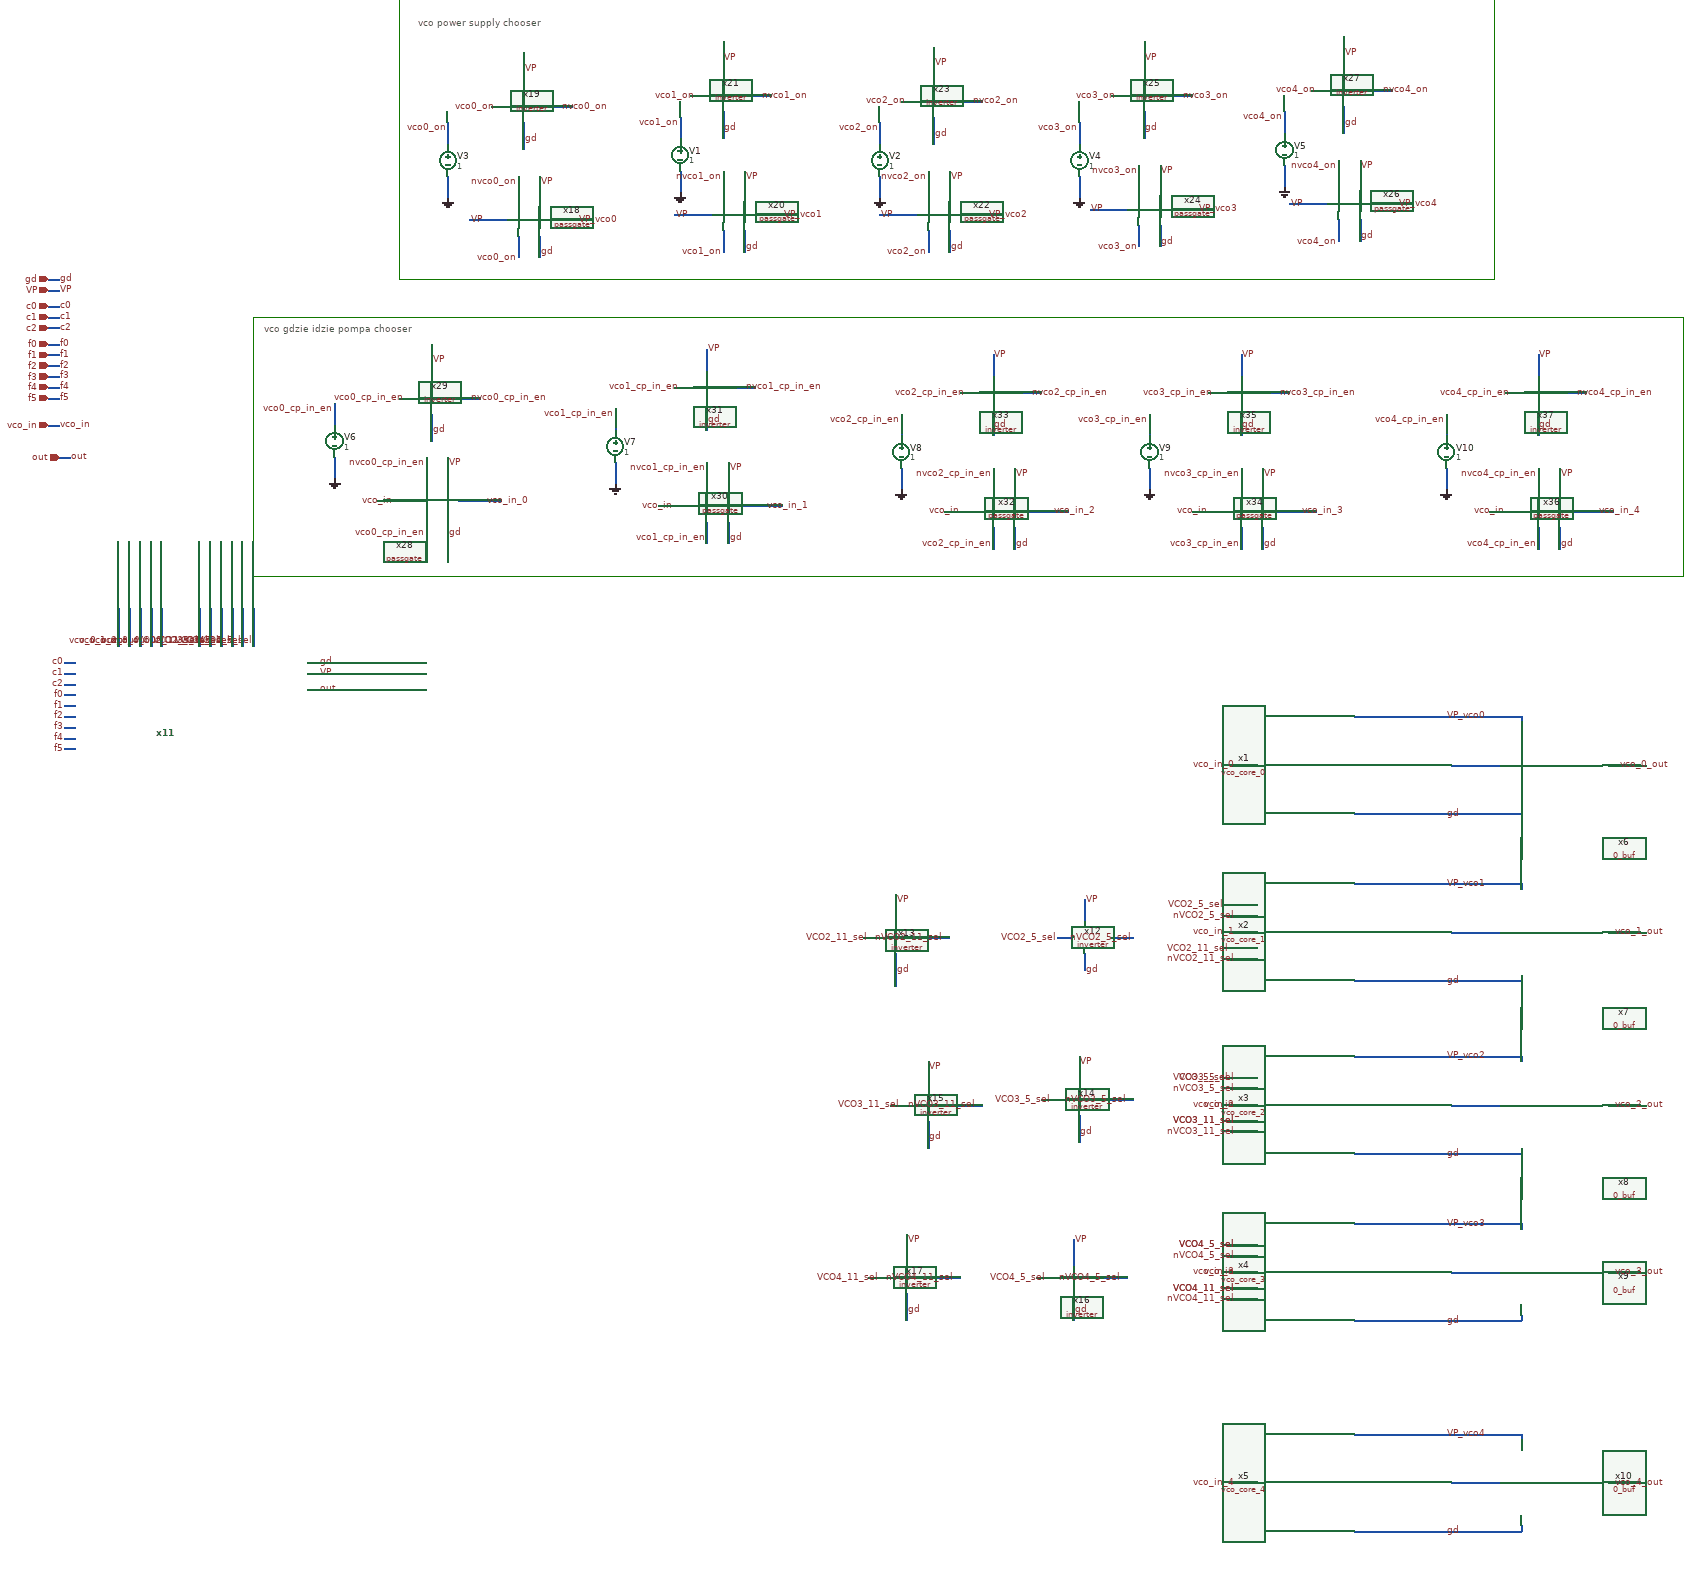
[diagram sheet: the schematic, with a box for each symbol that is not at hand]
v {xschem version=3.4.8RC file_version=1.3}
G {}
K {}
V {}
S {}
F {}
E {}
L 4 -1290 -780 -1290 -340 {}
L 4 -1290 -340 740 -340 {}
L 4 740 -860 740 -340 {}
L 4 -1290 -860 740 -860 {}
L 4 -1290 -860 -1290 -780 {}
P 4 6 -1560 -250 -1560 210 1090 210 1090 -270 -1560 -270 -1560 -250 {}
T {vco power supply chooser} -1253.835345354359 -827.5054171371571 0 0 0.4 0.4 {}
T {vco gdzie idzie pompa chooser} -1540 -260 0 0 0.4 0.4 {}
N 660 560 750 560 {lab=#net1}
N 660 870 750 870 {lab=#net2}
N 660 1190 750 1190 {lab=#net3}
N 660 1500 750 1500 {lab=#net4}
N 660 1890 750 1890 {lab=#net5}
N 950 560 1010 560 {lab=vco_0_out}
N 950 870 1010 870 {lab=vco_1_out}
N 950 1190 1010 1190 {lab=vco_2_out}
N 950 1500 1010 1500 {lab=vco_3_out}
N 950 1890 1010 1890 {lab=vco_4_out}
N -1940 -340 -1920 -340 {lab=gd}
N -1940 -320 -1920 -320 {lab=VP}
N -1940 -270 -1920 -270 {lab=c1}
N -1940 -250 -1920 -250 {lab=c2}
N -1940 -220 -1920 -220 {lab=f0}
N -1940 -200 -1920 -200 {lab=f1}
N -1940 -290 -1920 -290 {lab=c0}
N -1940 -180 -1920 -180 {lab=f2}
N -1940 -160 -1920 -160 {lab=f3}
N -1940 -140 -1920 -140 {lab=f4}
N -1940 -120 -1920 -120 {lab=f5}
N -1460 370 -1440 370 {lab=gd}
N -1460 390 -1440 390 {lab=VP}
N -1920 -10 -1900 -10 {lab=out}
N -1460 420 -1440 420 {lab=out}
N 480 650 790 650 {lab=gd}
N 790 640 790 650 {lab=gd}
N 480 960 790 960 {lab=gd}
N 790 950 790 960 {lab=gd}
N 480 1280 790 1280 {lab=gd}
N 790 1270 790 1280 {lab=gd}
N 790 1580 790 1590 {lab=gd}
N 480 1980 790 1980 {lab=gd}
N 790 1970 790 1980 {lab=gd}
N 480 1800 790 1800 {lab=VP_vco4}
N 790 1800 790 1810 {lab=VP_vco4}
N 480 1410 790 1410 {lab=VP_vco3}
N 790 1410 790 1420 {lab=VP_vco3}
N 480 1100 790 1100 {lab=VP_vco2}
N 790 1100 790 1110 {lab=VP_vco2}
N 480 780 790 780 {lab=VP_vco1}
N 790 780 790 790 {lab=VP_vco1}
N 480 470 790 470 {lab=VP_vco0}
N 790 470 790 480 {lab=VP_vco0}
N 250 900 300 900 {lab=VCO2_11_sel}
N 250 920 300 920 {lab=nVCO2_11_sel}
N 250 1240 300 1240 {lab=nVCO3_11_sel}
N 250 1550 300 1550 {lab=nVCO4_11_sel}
N 250 1890 300 1890 {lab=vco_in}
N 250 560 300 560 {lab=#net6}
N -1660 270 -1660 340 {lab=VCO2_11_sel}
N -1640 270 -1640 340 {lab=VCO2_5_sel}
N -1620 270 -1620 340 {lab=VCO3_11_sel}
N -1600 270 -1600 340 {lab=VCO3_5_sel}
N -1580 270 -1580 340 {lab=VCO4_11_sel}
N -1560 270 -1560 340 {lab=VCO4_5_sel}
N -1810 270 -1810 340 {lab=vco_0_out}
N -1790 270 -1790 340 {lab=vco_1_out}
N -1770 270 -1770 340 {lab=vco_2_out}
N -1750 270 -1750 340 {lab=vco_3_out}
N -1730 270 -1730 340 {lab=vco_4_out}
N -1910 390 -1890 390 {lab=c1}
N -1910 410 -1890 410 {lab=c2}
N -1910 430 -1890 430 {lab=f0}
N -1910 450 -1890 450 {lab=f1}
N -1910 370 -1890 370 {lab=c0}
N -1910 470 -1890 470 {lab=f2}
N -1910 490 -1890 490 {lab=f3}
N -1910 510 -1890 510 {lab=f4}
N -1910 530 -1890 530 {lab=f5}
N -1940 -70 -1920 -70 {lab=vco_in}
N 250 1500 300 1500 {lab=vco_in}
N 250 1190 300 1190 {lab=vco_in}
N 250 870 300 870 {lab=vco_in}
N 480 1590 790 1590 {lab=gd}
N 250 840 300 840 {lab=nVCO2_5_sel}
N 250 1140 300 1140 {lab=VCO3_5_sel}
N 250 1160 300 1160 {lab=nVCO3_5_sel}
N -30 1100 -30 1150 {lab=VP}
N -30 1210 -30 1260 {lab=gd}
N 20 1180 70 1180 {lab=nVCO3_5_sel}
N -100 1180 -50 1180 {lab=VCO3_5_sel}
N -310 1110 -310 1160 {lab=VP}
N -310 1220 -310 1270 {lab=gd}
N -260 1190 -210 1190 {lab=nVCO3_11_sel}
N -380 1190 -330 1190 {lab=VCO3_11_sel}
N 250 1450 300 1450 {lab=VCO4_5_sel}
N 250 1530 300 1530 {lab=VCO4_11_sel}
N 250 1470 300 1470 {lab=nVCO4_5_sel}
N -40 1540 -40 1590 {lab=gd}
N 10 1510 60 1510 {lab=nVCO4_5_sel}
N -110 1510 -60 1510 {lab=VCO4_5_sel}
N -350 1430 -350 1480 {lab=VP}
N -350 1540 -350 1590 {lab=gd}
N -300 1510 -250 1510 {lab=nVCO4_11_sel}
N -420 1510 -370 1510 {lab=VCO4_11_sel}
N -40 1440 -40 1490 {lab=VP}
N -1160 -450 -1090 -450 {lab=VP}
N -1010 -450 -930 -450 {lab=VP_vco0}
N -1120 -660 -1080 -660 {lab=vco0_on}
N -1060 -630 -1060 -580 {lab=gd}
N -1060 -760 -1060 -690 {lab=VP}
N -1010 -660 -970 -660 {lab=nvco0_on}
N -1070 -420 -1070 -380 {lab=vco0_on}
N -1070 -530 -1070 -480 {lab=nvco0_on}
N -1030 -530 -1030 -480 {lab=VP}
N -1030 -420 -1030 -380 {lab=gd}
N -780 -460 -710 -460 {lab=VP}
N -630 -460 -550 -460 {lab=VP_vco1}
N -750 -680 -710 -680 {lab=vco1_on}
N -690 -650 -690 -600 {lab=gd}
N -690 -780 -690 -710 {lab=VP}
N -640 -680 -600 -680 {lab=nvco1_on}
N -690 -430 -690 -390 {lab=vco1_on}
N -690 -540 -690 -490 {lab=nvco1_on}
N -650 -540 -650 -490 {lab=VP}
N -650 -430 -650 -390 {lab=gd}
N -400 -460 -330 -460 {lab=VP}
N -250 -460 -170 -460 {lab=VP_vco2}
N -360 -670 -320 -670 {lab=vco2_on}
N -300 -640 -300 -590 {lab=gd}
N -300 -770 -300 -700 {lab=VP}
N -250 -670 -210 -670 {lab=nvco2_on}
N -310 -430 -310 -390 {lab=vco2_on}
N -310 -540 -310 -490 {lab=nvco2_on}
N -270 -540 -270 -490 {lab=VP}
N -270 -430 -270 -390 {lab=gd}
N -10 -470 60 -470 {lab=VP}
N 140 -470 220 -470 {lab=VP_vco3}
N 30 -680 70 -680 {lab=vco3_on}
N 90 -650 90 -600 {lab=gd}
N 90 -780 90 -710 {lab=VP}
N 140 -680 180 -680 {lab=nvco3_on}
N 80 -440 80 -400 {lab=vco3_on}
N 80 -550 80 -500 {lab=nvco3_on}
N 120 -550 120 -500 {lab=VP}
N 120 -440 120 -400 {lab=gd}
N 360 -480 430 -480 {lab=VP}
N 510 -480 590 -480 {lab=VP_vco4}
N 400 -690 440 -690 {lab=vco4_on}
N 460 -660 460 -610 {lab=gd}
N 460 -790 460 -720 {lab=VP}
N 510 -690 550 -690 {lab=nvco4_on}
N 450 -450 450 -410 {lab=vco4_on}
N 450 -560 450 -510 {lab=nvco4_on}
N 490 -560 490 -510 {lab=VP}
N 490 -450 490 -410 {lab=gd}
N -1200 -530 -1200 -490 {lab=0}
N -1200 -630 -1200 -590 {lab=vco0_on}
N -770 -540 -770 -500 {lab=0}
N -770 -640 -770 -600 {lab=vco1_on}
N -400 -530 -400 -490 {lab=0}
N -400 -630 -400 -590 {lab=vco2_on}
N -30 -530 -30 -490 {lab=0}
N -30 -630 -30 -590 {lab=vco3_on}
N 350 -550 350 -510 {lab=0}
N 350 -650 350 -610 {lab=vco4_on}
N 240 820 300 820 {lab=VCO2_5_sel}
N 250 1220 300 1220 {lab=VCO3_11_sel}
N -20 810 -20 850 {lab=VP}
N -70 880 -40 880 {lab=VCO2_5_sel}
N 30 880 70 880 {lab=nVCO2_5_sel}
N -20 910 -20 940 {lab=gd}
N -370 800 -370 850 {lab=VP}
N -370 910 -370 970 {lab=gd}
N -320 880 -270 880 {lab=nVCO2_11_sel}
N -430 880 -390 880 {lab=VCO2_11_sel}
N -1330 70 -1260 70 {lab=vco_in}
N -1180 70 -1100 70 {lab=vco_in_0}
N -1290 -120 -1250 -120 {lab=vco0_cp_in_en}
N -1230 -90 -1230 -40 {lab=gd}
N -1230 -220 -1230 -150 {lab=VP}
N -1180 -120 -1140 -120 {lab=nvco0_cp_in_en}
N -1240 100 -1240 140 {lab=vco0_cp_in_en}
N -1240 -10 -1240 40 {lab=nvco0_cp_in_en}
N -1200 -10 -1200 40 {lab=VP}
N -1200 100 -1200 140 {lab=gd}
N -1410 -10 -1410 30 {lab=0}
N -1410 -110 -1410 -70 {lab=vco0_cp_in_en}
N -810 80 -740 80 {lab=vco_in}
N -660 80 -580 80 {lab=vco_in_1}
N -780 -140 -740 -140 {lab=vco1_cp_in_en}
N -720 -110 -720 -60 {lab=gd}
N -670 -140 -630 -140 {lab=nvco1_cp_in_en}
N -720 110 -720 150 {lab=vco1_cp_in_en}
N -720 0 -720 50 {lab=nvco1_cp_in_en}
N -680 0 -680 50 {lab=VP}
N -680 110 -680 150 {lab=gd}
N -890 0 -890 40 {lab=0}
N -890 -100 -890 -60 {lab=vco1_cp_in_en}
N -720 -210 -720 -170 {lab=VP}
N -280 90 -210 90 {lab=vco_in}
N -130 90 -50 90 {lab=vco_in_1}
N -250 -130 -210 -130 {lab=vco1_cp_in_en}
N -190 -100 -190 -50 {lab=gd}
N -140 -130 -100 -130 {lab=nvco1_cp_in_en}
N -190 120 -190 160 {lab=vco1_cp_in_en}
N -190 10 -190 60 {lab=nvco1_cp_in_en}
N -150 10 -150 60 {lab=VP}
N -150 120 -150 160 {lab=gd}
N -360 10 -360 50 {lab=0}
N -360 -90 -360 -50 {lab=vco1_cp_in_en}
N -190 -200 -190 -160 {lab=VP}
N 180 90 250 90 {lab=vco_in}
N 330 90 410 90 {lab=vco_in_1}
N 210 -130 250 -130 {lab=vco1_cp_in_en}
N 270 -100 270 -50 {lab=gd}
N 320 -130 360 -130 {lab=nvco1_cp_in_en}
N 270 120 270 160 {lab=vco1_cp_in_en}
N 270 10 270 60 {lab=nvco1_cp_in_en}
N 310 10 310 60 {lab=VP}
N 310 120 310 160 {lab=gd}
N 100 10 100 50 {lab=0}
N 100 -90 100 -50 {lab=vco1_cp_in_en}
N 270 -200 270 -160 {lab=VP}
N 730 90 800 90 {lab=vco_in}
N 880 90 960 90 {lab=vco_in_1}
N 760 -130 800 -130 {lab=vco1_cp_in_en}
N 820 -100 820 -50 {lab=gd}
N 870 -130 910 -130 {lab=nvco1_cp_in_en}
N 820 120 820 160 {lab=vco1_cp_in_en}
N 820 10 820 60 {lab=nvco1_cp_in_en}
N 860 10 860 60 {lab=VP}
N 860 120 860 160 {lab=gd}
N 650 10 650 50 {lab=0}
N 650 -90 650 -50 {lab=vco1_cp_in_en}
N 820 -200 820 -160 {lab=VP}
C {/foss/designs/CHIP-PLL/schematics/vco/vco_cell/vco_core_0.sym} 480 560 0 0 {name=x1}
C {/foss/designs/CHIP-PLL/schematics/vco/vco_cell/vco_core_1.sym} 480 870 0 0 {name=x2}
C {/foss/designs/CHIP-PLL/schematics/vco/vco_cell/vco_core_2.sym} 480 1190 0 0 {name=x3}
C {/foss/designs/CHIP-PLL/schematics/vco/vco_cell/vco_core_3.sym} 480 1500 0 0 {name=x4}
C {/foss/designs/CHIP-PLL/schematics/vco/vco_cell/vco_core_4.sym} 480 1890 0 0 {name=x5}
C {/foss/designs/CHIP-PLL/schematics/vco/vco_cell/0_buf.sym} 830 650 0 0 {name=x6}
C {/foss/designs/CHIP-PLL/schematics/vco/vco_cell/0_buf.sym} 830 960 0 0 {name=x7}
C {/foss/designs/CHIP-PLL/schematics/vco/vco_cell/0_buf.sym} 830 1280 0 0 {name=x8}
C {/foss/designs/CHIP-PLL/schematics/vco/vco_cell/0_buf.sym} 830 1590 0 0 {name=x9}
C {/foss/designs/CHIP-PLL/schematics/vco/vco_cell/0_buf.sym} 830 1980 0 0 {name=x10}
C {/foss/designs/CHIP-PLL/schematics/divider/schematics/VCO_MUX_and_decoder.sym} -1740 500 0 0 {name=x11}
C {iopin.sym} -1940 -340 2 0 {name=p46 lab=gd}
C {lab_wire.sym} -1920 -340 2 0 {name=p53 sig_type=std_logic lab=gd}
C {iopin.sym} -1940 -320 2 0 {name=p54 lab=VP}
C {ipin.sym} -1940 -270 0 0 {name=p2 lab=c1}
C {lab_wire.sym} -1920 -270 2 0 {name=p56 sig_type=std_logic lab=c1}
C {ipin.sym} -1940 -250 0 0 {name=p57 lab=c2}
C {lab_wire.sym} -1920 -250 2 0 {name=p58 sig_type=std_logic lab=c2}
C {ipin.sym} -1940 -220 0 0 {name=p59 lab=f0}
C {lab_wire.sym} -1920 -220 2 0 {name=p60 sig_type=std_logic lab=f0}
C {ipin.sym} -1940 -200 0 0 {name=p61 lab=f1}
C {lab_wire.sym} -1920 -200 2 0 {name=p63 sig_type=std_logic lab=f1}
C {ipin.sym} -1940 -290 0 0 {name=p20 lab=c0}
C {lab_wire.sym} -1920 -290 2 0 {name=p21 sig_type=std_logic lab=c0}
C {lab_wire.sym} -1920 -320 2 0 {name=p1 sig_type=std_logic lab=VP}
C {ipin.sym} -1940 -180 0 0 {name=p19 lab=f2}
C {lab_wire.sym} -1920 -180 2 0 {name=p22 sig_type=std_logic lab=f2}
C {ipin.sym} -1940 -160 0 0 {name=p23 lab=f3}
C {lab_wire.sym} -1920 -160 2 0 {name=p24 sig_type=std_logic lab=f3}
C {ipin.sym} -1940 -140 0 0 {name=p25 lab=f4}
C {lab_wire.sym} -1920 -140 2 0 {name=p26 sig_type=std_logic lab=f4}
C {ipin.sym} -1940 -120 0 0 {name=p27 lab=f5}
C {lab_wire.sym} -1920 -120 2 0 {name=p28 sig_type=std_logic lab=f5}
C {lab_wire.sym} -1440 370 2 0 {name=p3 sig_type=std_logic lab=gd}
C {lab_wire.sym} -1440 390 2 0 {name=p4 sig_type=std_logic lab=VP}
C {opin.sym} -1920 -10 0 1 {name=p55 lab=out}
C {lab_wire.sym} -1900 -10 2 0 {name=p62 sig_type=std_logic lab=out}
C {lab_wire.sym} -1440 420 2 0 {name=p5 sig_type=std_logic lab=out}
C {lab_wire.sym} 650 780 2 0 {name=p6 sig_type=std_logic lab=VP_vco1}
C {lab_wire.sym} 650 470 2 0 {name=p7 sig_type=std_logic lab=VP_vco0}
C {lab_wire.sym} 650 1100 2 0 {name=p8 sig_type=std_logic lab=VP_vco2}
C {lab_wire.sym} 650 1410 2 0 {name=p9 sig_type=std_logic lab=VP_vco3}
C {lab_wire.sym} 650 1800 2 0 {name=p10 sig_type=std_logic lab=VP_vco4}
C {lab_wire.sym} 650 650 2 0 {name=p11 sig_type=std_logic lab=gd}
C {lab_wire.sym} 650 960 2 0 {name=p12 sig_type=std_logic lab=gd}
C {lab_wire.sym} 650 1280 2 0 {name=p13 sig_type=std_logic lab=gd}
C {lab_wire.sym} 650 1590 2 0 {name=p14 sig_type=std_logic lab=gd}
C {lab_wire.sym} 650 1980 2 0 {name=p15 sig_type=std_logic lab=gd}
C {lab_wire.sym} 250 900 2 1 {name=p95 sig_type=std_logic lab=VCO2_11_sel}
C {lab_wire.sym} 240 820 2 1 {name=p99 sig_type=std_logic lab=VCO2_5_sel}
C {lab_wire.sym} 260 1220 2 1 {name=p16 sig_type=std_logic lab=VCO3_11_sel}
C {lab_wire.sym} 250 1140 2 1 {name=p17 sig_type=std_logic lab=VCO3_5_sel}
C {lab_wire.sym} 260 1530 2 1 {name=p18 sig_type=std_logic lab=VCO4_11_sel}
C {lab_wire.sym} 260 1450 2 1 {name=p29 sig_type=std_logic lab=VCO4_5_sel}
C {lab_wire.sym} -1660 330 3 1 {name=p33 sig_type=std_logic lab=VCO2_11_sel}
C {lab_wire.sym} -1640 330 3 1 {name=p35 sig_type=std_logic lab=VCO2_5_sel}
C {lab_wire.sym} -1620 330 3 1 {name=p36 sig_type=std_logic lab=VCO3_11_sel}
C {lab_wire.sym} -1600 330 3 1 {name=p37 sig_type=std_logic lab=VCO3_5_sel}
C {lab_wire.sym} -1580 330 3 1 {name=p38 sig_type=std_logic lab=VCO4_11_sel}
C {lab_wire.sym} -1560 330 3 1 {name=p39 sig_type=std_logic lab=VCO4_5_sel}
C {lab_wire.sym} 970 560 2 0 {name=p34 sig_type=std_logic lab=vco_0_out}
C {lab_wire.sym} 960 870 2 0 {name=p41 sig_type=std_logic lab=vco_1_out}
C {lab_wire.sym} 960 1190 2 0 {name=p42 sig_type=std_logic lab=vco_2_out}
C {lab_wire.sym} 960 1500 2 0 {name=p43 sig_type=std_logic lab=vco_3_out}
C {lab_wire.sym} 960 1890 2 0 {name=p44 sig_type=std_logic lab=vco_4_out}
C {lab_wire.sym} -1810 330 3 1 {name=p45 sig_type=std_logic lab=vco_0_out}
C {lab_wire.sym} -1790 330 3 1 {name=p47 sig_type=std_logic lab=vco_1_out}
C {lab_wire.sym} -1770 330 3 1 {name=p48 sig_type=std_logic lab=vco_2_out}
C {lab_wire.sym} -1750 330 3 1 {name=p49 sig_type=std_logic lab=vco_3_out}
C {lab_wire.sym} -1730 330 3 1 {name=p50 sig_type=std_logic lab=vco_4_out}
C {lab_wire.sym} -1910 390 2 1 {name=p51 sig_type=std_logic lab=c1}
C {lab_wire.sym} -1910 410 2 1 {name=p52 sig_type=std_logic lab=c2}
C {lab_wire.sym} -1910 430 2 1 {name=p64 sig_type=std_logic lab=f0}
C {lab_wire.sym} -1910 450 2 1 {name=p65 sig_type=std_logic lab=f1}
C {lab_wire.sym} -1910 370 2 1 {name=p66 sig_type=std_logic lab=c0}
C {lab_wire.sym} -1910 470 2 1 {name=p67 sig_type=std_logic lab=f2}
C {lab_wire.sym} -1910 490 2 1 {name=p68 sig_type=std_logic lab=f3}
C {lab_wire.sym} -1910 510 2 1 {name=p69 sig_type=std_logic lab=f4}
C {lab_wire.sym} -1910 530 2 1 {name=p70 sig_type=std_logic lab=f5}
C {ipin.sym} -1940 -70 0 0 {name=p30 lab=vco_in}
C {lab_wire.sym} -1920 -70 2 0 {name=p31 sig_type=std_logic lab=vco_in}
C {lab_wire.sym} -1300 70 2 1 {name=p71 sig_type=std_logic lab=vco_in}
C {lab_wire.sym} 260 870 2 1 {name=p72 sig_type=std_logic lab=vco_in_1}
C {lab_wire.sym} 260 1190 2 1 {name=p73 sig_type=std_logic lab=vco_in_2}
C {lab_wire.sym} 260 1500 2 1 {name=p74 sig_type=std_logic lab=vco_in_3}
C {lab_wire.sym} 260 1890 2 1 {name=p75 sig_type=std_logic lab=vco_in_4}
C {/foss/designs/CHIP-PLL/schematics/divider/schematics/inverter.sym} -20 880 0 0 {name=x12}
C {lab_wire.sym} -20 810 2 0 {name=p32 sig_type=std_logic lab=VP}
C {lab_wire.sym} -20 940 2 0 {name=p40 sig_type=std_logic lab=gd}
C {lab_wire.sym} -70 880 2 1 {name=p76 sig_type=std_logic lab=VCO2_5_sel}
C {lab_wire.sym} 70 880 2 1 {name=p77 sig_type=std_logic lab=nVCO2_5_sel}
C {lab_wire.sym} 260 840 2 1 {name=p78 sig_type=std_logic lab=nVCO2_5_sel}
C {/foss/designs/CHIP-PLL/schematics/divider/schematics/inverter.sym} -370 880 0 0 {name=x13}
C {lab_wire.sym} -370 810 2 0 {name=p79 sig_type=std_logic lab=VP}
C {lab_wire.sym} -370 940 2 0 {name=p80 sig_type=std_logic lab=gd}
C {lab_wire.sym} -420 880 2 1 {name=p81 sig_type=std_logic lab=VCO2_11_sel}
C {lab_wire.sym} -280 880 2 1 {name=p82 sig_type=std_logic lab=nVCO2_11_sel}
C {lab_wire.sym} 260 920 2 1 {name=p83 sig_type=std_logic lab=nVCO2_11_sel}
C {lab_wire.sym} 260 1220 2 1 {name=p16 sig_type=std_logic lab=VCO3_11_sel}
C {lab_wire.sym} 260 1140 2 1 {name=p17 sig_type=std_logic lab=VCO3_5_sel}
C {lab_wire.sym} 260 1190 2 1 {name=p18 sig_type=std_logic lab=vco_in}
C {lab_wire.sym} 260 1160 2 1 {name=p29 sig_type=std_logic lab=nVCO3_5_sel}
C {lab_wire.sym} 260 1240 2 1 {name=p73 sig_type=std_logic lab=nVCO3_11_sel}
C {/foss/designs/CHIP-PLL/schematics/divider/schematics/inverter.sym} -30 1180 0 0 {name=x14}
C {lab_wire.sym} -30 1110 2 0 {name=p74 sig_type=std_logic lab=VP}
C {lab_wire.sym} -30 1240 2 0 {name=p84 sig_type=std_logic lab=gd}
C {lab_wire.sym} -80 1180 2 1 {name=p85 sig_type=std_logic lab=VCO3_5_sel}
C {lab_wire.sym} 60 1180 2 1 {name=p86 sig_type=std_logic lab=nVCO3_5_sel}
C {/foss/designs/CHIP-PLL/schematics/divider/schematics/inverter.sym} -310 1190 0 0 {name=x15}
C {lab_wire.sym} -310 1120 2 0 {name=p87 sig_type=std_logic lab=VP}
C {lab_wire.sym} -310 1250 2 0 {name=p88 sig_type=std_logic lab=gd}
C {lab_wire.sym} -360 1190 2 1 {name=p89 sig_type=std_logic lab=VCO3_11_sel}
C {lab_wire.sym} -220 1190 2 1 {name=p90 sig_type=std_logic lab=nVCO3_11_sel}
C {lab_wire.sym} 260 1530 2 1 {name=p91 sig_type=std_logic lab=VCO4_11_sel}
C {lab_wire.sym} 260 1450 2 1 {name=p92 sig_type=std_logic lab=VCO4_5_sel}
C {lab_wire.sym} 260 1500 2 1 {name=p93 sig_type=std_logic lab=vco_in}
C {lab_wire.sym} 260 1470 2 1 {name=p94 sig_type=std_logic lab=nVCO4_5_sel}
C {lab_wire.sym} 260 1550 2 1 {name=p96 sig_type=std_logic lab=nVCO4_11_sel}
C {/foss/designs/CHIP-PLL/schematics/divider/schematics/inverter.sym} -40 1510 0 0 {name=x16}
C {lab_wire.sym} -40 1440 2 0 {name=p97 sig_type=std_logic lab=VP}
C {lab_wire.sym} -40 1570 2 0 {name=p98 sig_type=std_logic lab=gd}
C {lab_wire.sym} -90 1510 2 1 {name=p100 sig_type=std_logic lab=VCO4_5_sel}
C {lab_wire.sym} 50 1510 2 1 {name=p101 sig_type=std_logic lab=nVCO4_5_sel}
C {/foss/designs/CHIP-PLL/schematics/divider/schematics/inverter.sym} -350 1510 0 0 {name=x17}
C {lab_wire.sym} -350 1440 2 0 {name=p102 sig_type=std_logic lab=VP}
C {lab_wire.sym} -350 1570 2 0 {name=p103 sig_type=std_logic lab=gd}
C {lab_wire.sym} -400 1510 2 1 {name=p104 sig_type=std_logic lab=VCO4_11_sel}
C {lab_wire.sym} -260 1510 2 1 {name=p105 sig_type=std_logic lab=nVCO4_11_sel}
C {/foss/designs/CHIP-PLL/schematics/divider/schematics/passgate.sym} -1070 -430 0 0 {name=x18}
C {/foss/designs/CHIP-PLL/schematics/divider/schematics/inverter.sym} -1060 -660 0 0 {name=x19}
C {lab_wire.sym} -1060 -730 2 0 {name=p107 sig_type=std_logic lab=VP}
C {lab_wire.sym} -1060 -600 2 0 {name=p108 sig_type=std_logic lab=gd}
C {lab_wire.sym} -990 -660 2 0 {name=p109 sig_type=std_logic lab=nvco0_on}
C {lab_wire.sym} -1030 -390 2 0 {name=p110 sig_type=std_logic lab=gd}
C {lab_wire.sym} -1030 -520 2 0 {name=p111 sig_type=std_logic lab=VP}
C {lab_wire.sym} -1160 -450 2 0 {name=p112 sig_type=std_logic lab=VP}
C {lab_wire.sym} -960 -450 2 0 {name=p113 sig_type=std_logic lab=VP_vco0}
C {lab_wire.sym} -1070 -380 2 1 {name=p114 sig_type=std_logic lab=vco0_on}
C {lab_wire.sym} -1070 -520 2 1 {name=p115 sig_type=std_logic lab=nvco0_on}
C {/foss/designs/CHIP-PLL/schematics/divider/schematics/passgate.sym} -690 -440 0 0 {name=x20}
C {/foss/designs/CHIP-PLL/schematics/divider/schematics/inverter.sym} -690 -680 0 0 {name=x21}
C {lab_wire.sym} -690 -750 2 0 {name=p117 sig_type=std_logic lab=VP}
C {lab_wire.sym} -690 -620 2 0 {name=p118 sig_type=std_logic lab=gd}
C {lab_wire.sym} -620 -680 2 0 {name=p119 sig_type=std_logic lab=nvco1_on}
C {lab_wire.sym} -650 -400 2 0 {name=p120 sig_type=std_logic lab=gd}
C {lab_wire.sym} -650 -530 2 0 {name=p121 sig_type=std_logic lab=VP}
C {lab_wire.sym} -780 -460 2 0 {name=p122 sig_type=std_logic lab=VP}
C {lab_wire.sym} -580 -460 2 0 {name=p123 sig_type=std_logic lab=VP_vco1}
C {lab_wire.sym} -690 -390 2 1 {name=p124 sig_type=std_logic lab=vco1_on}
C {lab_wire.sym} -690 -530 2 1 {name=p125 sig_type=std_logic lab=nvco1_on}
C {/foss/designs/CHIP-PLL/schematics/divider/schematics/passgate.sym} -310 -440 0 0 {name=x22}
C {/foss/designs/CHIP-PLL/schematics/divider/schematics/inverter.sym} -300 -670 0 0 {name=x23}
C {lab_wire.sym} -300 -740 2 0 {name=p127 sig_type=std_logic lab=VP}
C {lab_wire.sym} -300 -610 2 0 {name=p128 sig_type=std_logic lab=gd}
C {lab_wire.sym} -230 -670 2 0 {name=p129 sig_type=std_logic lab=nvco2_on}
C {lab_wire.sym} -270 -400 2 0 {name=p130 sig_type=std_logic lab=gd}
C {lab_wire.sym} -270 -530 2 0 {name=p131 sig_type=std_logic lab=VP}
C {lab_wire.sym} -400 -460 2 0 {name=p132 sig_type=std_logic lab=VP}
C {lab_wire.sym} -200 -460 2 0 {name=p133 sig_type=std_logic lab=VP_vco2}
C {lab_wire.sym} -310 -390 2 1 {name=p134 sig_type=std_logic lab=vco2_on}
C {lab_wire.sym} -310 -530 2 1 {name=p135 sig_type=std_logic lab=nvco2_on}
C {/foss/designs/CHIP-PLL/schematics/divider/schematics/passgate.sym} 80 -450 0 0 {name=x24}
C {/foss/designs/CHIP-PLL/schematics/divider/schematics/inverter.sym} 90 -680 0 0 {name=x25}
C {lab_wire.sym} 90 -750 2 0 {name=p137 sig_type=std_logic lab=VP}
C {lab_wire.sym} 90 -620 2 0 {name=p138 sig_type=std_logic lab=gd}
C {lab_wire.sym} 160 -680 2 0 {name=p139 sig_type=std_logic lab=nvco3_on}
C {lab_wire.sym} 120 -410 2 0 {name=p140 sig_type=std_logic lab=gd}
C {lab_wire.sym} 120 -540 2 0 {name=p141 sig_type=std_logic lab=VP}
C {lab_wire.sym} -10 -470 2 0 {name=p142 sig_type=std_logic lab=VP}
C {lab_wire.sym} 190 -470 2 0 {name=p143 sig_type=std_logic lab=VP_vco3}
C {lab_wire.sym} 80 -400 2 1 {name=p144 sig_type=std_logic lab=vco3_on}
C {lab_wire.sym} 80 -540 2 1 {name=p145 sig_type=std_logic lab=nvco3_on}
C {/foss/designs/CHIP-PLL/schematics/divider/schematics/passgate.sym} 450 -460 0 0 {name=x26}
C {/foss/designs/CHIP-PLL/schematics/divider/schematics/inverter.sym} 460 -690 0 0 {name=x27}
C {lab_wire.sym} 460 -760 2 0 {name=p147 sig_type=std_logic lab=VP}
C {lab_wire.sym} 460 -630 2 0 {name=p148 sig_type=std_logic lab=gd}
C {lab_wire.sym} 530 -690 2 0 {name=p149 sig_type=std_logic lab=nvco4_on}
C {lab_wire.sym} 490 -420 2 0 {name=p150 sig_type=std_logic lab=gd}
C {lab_wire.sym} 490 -550 2 0 {name=p151 sig_type=std_logic lab=VP}
C {lab_wire.sym} 360 -480 2 0 {name=p152 sig_type=std_logic lab=VP}
C {lab_wire.sym} 560 -480 2 0 {name=p153 sig_type=std_logic lab=VP_vco4}
C {lab_wire.sym} 450 -410 2 1 {name=p154 sig_type=std_logic lab=vco4_on}
C {lab_wire.sym} 450 -550 2 1 {name=p155 sig_type=std_logic lab=nvco4_on}
C {lab_wire.sym} -1110 -660 2 1 {name=p106 sig_type=std_logic lab=vco0_on}
C {lab_wire.sym} -740 -680 2 1 {name=p116 sig_type=std_logic lab=vco1_on}
C {lab_wire.sym} -350 -670 2 1 {name=p126 sig_type=std_logic lab=vco2_on}
C {lab_wire.sym} 40 -680 2 1 {name=p136 sig_type=std_logic lab=vco3_on}
C {lab_wire.sym} 410 -690 2 1 {name=p146 sig_type=std_logic lab=vco4_on}
C {vsource.sym} -1200 -560 0 0 {name=V3 value=1 savecurrent=false}
C {gnd.sym} -1200 -490 0 0 {name=l1 lab=0
}
C {lab_wire.sym} -1200 -620 2 1 {name=p156 sig_type=std_logic lab=vco0_on}
C {vsource.sym} -770 -570 0 0 {name=V1 value=1 savecurrent=false}
C {gnd.sym} -770 -500 0 0 {name=l2 lab=0
}
C {lab_wire.sym} -770 -630 2 1 {name=p157 sig_type=std_logic lab=vco1_on}
C {vsource.sym} -400 -560 0 0 {name=V2 value=1 savecurrent=false}
C {gnd.sym} -400 -490 0 0 {name=l3 lab=0
}
C {lab_wire.sym} -400 -620 2 1 {name=p158 sig_type=std_logic lab=vco2_on}
C {vsource.sym} -30 -560 0 0 {name=V4 value=1 savecurrent=false}
C {gnd.sym} -30 -490 0 0 {name=l4 lab=0
}
C {lab_wire.sym} -30 -620 2 1 {name=p159 sig_type=std_logic lab=vco3_on}
C {vsource.sym} 350 -580 0 0 {name=V5 value=1 savecurrent=false}
C {gnd.sym} 350 -510 0 0 {name=l5 lab=0
}
C {lab_wire.sym} 350 -640 2 1 {name=p160 sig_type=std_logic lab=vco4_on}
C {/foss/designs/CHIP-PLL/schematics/divider/schematics/passgate.sym} -1240 90 0 0 {name=x28}
C {/foss/designs/CHIP-PLL/schematics/divider/schematics/inverter.sym} -1230 -120 0 0 {name=x29}
C {lab_wire.sym} -1230 -190 2 0 {name=p161 sig_type=std_logic lab=VP}
C {lab_wire.sym} -1230 -60 2 0 {name=p162 sig_type=std_logic lab=gd}
C {lab_wire.sym} -1200 130 2 0 {name=p164 sig_type=std_logic lab=gd}
C {lab_wire.sym} -1200 0 2 0 {name=p165 sig_type=std_logic lab=VP}
C {lab_wire.sym} -1130 70 2 0 {name=p167 sig_type=std_logic lab=vco_in_0}
C {lab_wire.sym} -1280 -120 2 1 {name=p170 sig_type=std_logic lab=vco0_cp_in_en}
C {vsource.sym} -1410 -40 0 0 {name=V6 value=1 savecurrent=false}
C {gnd.sym} -1410 30 0 0 {name=l6 lab=0
}
C {lab_wire.sym} -1160 -120 2 0 {name=p163 sig_type=std_logic lab=nvco0_cp_in_en}
C {lab_wire.sym} -1410 -100 2 1 {name=p166 sig_type=std_logic lab=vco0_cp_in_en}
C {lab_wire.sym} -1240 130 2 1 {name=p168 sig_type=std_logic lab=vco0_cp_in_en}
C {lab_wire.sym} -1240 0 2 1 {name=p169 sig_type=std_logic lab=nvco0_cp_in_en}
C {lab_wire.sym} -780 80 2 1 {name=p171 sig_type=std_logic lab=vco_in}
C {/foss/designs/CHIP-PLL/schematics/divider/schematics/passgate.sym} -720 100 0 0 {name=x30}
C {/foss/designs/CHIP-PLL/schematics/divider/schematics/inverter.sym} -720 -140 0 0 {name=x31}
C {lab_wire.sym} -720 -210 2 0 {name=p172 sig_type=std_logic lab=VP}
C {lab_wire.sym} -720 -80 2 0 {name=p173 sig_type=std_logic lab=gd}
C {lab_wire.sym} -680 140 2 0 {name=p174 sig_type=std_logic lab=gd}
C {lab_wire.sym} -680 10 2 0 {name=p175 sig_type=std_logic lab=VP}
C {lab_wire.sym} -610 80 2 0 {name=p176 sig_type=std_logic lab=vco_in_1}
C {lab_wire.sym} -770 -140 2 1 {name=p177 sig_type=std_logic lab=vco1_cp_in_en}
C {vsource.sym} -890 -30 0 0 {name=V7 value=1 savecurrent=false}
C {gnd.sym} -890 40 0 0 {name=l7 lab=0
}
C {lab_wire.sym} -650 -140 2 0 {name=p178 sig_type=std_logic lab=nvco1_cp_in_en}
C {lab_wire.sym} -890 -90 2 1 {name=p179 sig_type=std_logic lab=vco1_cp_in_en}
C {lab_wire.sym} -720 140 2 1 {name=p180 sig_type=std_logic lab=vco1_cp_in_en}
C {lab_wire.sym} -720 10 2 1 {name=p181 sig_type=std_logic lab=nvco1_cp_in_en}
C {lab_wire.sym} -250 90 2 1 {name=p182 sig_type=std_logic lab=vco_in}
C {/foss/designs/CHIP-PLL/schematics/divider/schematics/passgate.sym} -190 110 0 0 {name=x32}
C {/foss/designs/CHIP-PLL/schematics/divider/schematics/inverter.sym} -190 -130 0 0 {name=x33}
C {lab_wire.sym} -190 -200 2 0 {name=p183 sig_type=std_logic lab=VP}
C {lab_wire.sym} -190 -70 2 0 {name=p184 sig_type=std_logic lab=gd}
C {lab_wire.sym} -150 150 2 0 {name=p185 sig_type=std_logic lab=gd}
C {lab_wire.sym} -150 20 2 0 {name=p186 sig_type=std_logic lab=VP}
C {lab_wire.sym} -80 90 2 0 {name=p187 sig_type=std_logic lab=vco_in_2}
C {lab_wire.sym} -240 -130 2 1 {name=p188 sig_type=std_logic lab=vco2_cp_in_en}
C {vsource.sym} -360 -20 0 0 {name=V8 value=1 savecurrent=false}
C {gnd.sym} -360 50 0 0 {name=l8 lab=0
}
C {lab_wire.sym} -120 -130 2 0 {name=p189 sig_type=std_logic lab=nvco2_cp_in_en}
C {lab_wire.sym} -360 -80 2 1 {name=p190 sig_type=std_logic lab=vco2_cp_in_en}
C {lab_wire.sym} -190 150 2 1 {name=p191 sig_type=std_logic lab=vco2_cp_in_en}
C {lab_wire.sym} -190 20 2 1 {name=p192 sig_type=std_logic lab=nvco2_cp_in_en}
C {lab_wire.sym} 210 90 2 1 {name=p193 sig_type=std_logic lab=vco_in}
C {/foss/designs/CHIP-PLL/schematics/divider/schematics/passgate.sym} 270 110 0 0 {name=x34}
C {/foss/designs/CHIP-PLL/schematics/divider/schematics/inverter.sym} 270 -130 0 0 {name=x35}
C {lab_wire.sym} 270 -200 2 0 {name=p194 sig_type=std_logic lab=VP}
C {lab_wire.sym} 270 -70 2 0 {name=p195 sig_type=std_logic lab=gd}
C {lab_wire.sym} 310 150 2 0 {name=p196 sig_type=std_logic lab=gd}
C {lab_wire.sym} 310 20 2 0 {name=p197 sig_type=std_logic lab=VP}
C {lab_wire.sym} 380 90 2 0 {name=p198 sig_type=std_logic lab=vco_in_3}
C {lab_wire.sym} 220 -130 2 1 {name=p199 sig_type=std_logic lab=vco3_cp_in_en}
C {vsource.sym} 100 -20 0 0 {name=V9 value=1 savecurrent=false}
C {gnd.sym} 100 50 0 0 {name=l9 lab=0
}
C {lab_wire.sym} 340 -130 2 0 {name=p200 sig_type=std_logic lab=nvco3_cp_in_en}
C {lab_wire.sym} 100 -80 2 1 {name=p201 sig_type=std_logic lab=vco3_cp_in_en}
C {lab_wire.sym} 270 150 2 1 {name=p202 sig_type=std_logic lab=vco3_cp_in_en}
C {lab_wire.sym} 270 20 2 1 {name=p203 sig_type=std_logic lab=nvco3_cp_in_en}
C {lab_wire.sym} 760 90 2 1 {name=p204 sig_type=std_logic lab=vco_in}
C {/foss/designs/CHIP-PLL/schematics/divider/schematics/passgate.sym} 820 110 0 0 {name=x36}
C {/foss/designs/CHIP-PLL/schematics/divider/schematics/inverter.sym} 820 -130 0 0 {name=x37}
C {lab_wire.sym} 820 -200 2 0 {name=p205 sig_type=std_logic lab=VP}
C {lab_wire.sym} 820 -70 2 0 {name=p206 sig_type=std_logic lab=gd}
C {lab_wire.sym} 860 150 2 0 {name=p207 sig_type=std_logic lab=gd}
C {lab_wire.sym} 860 20 2 0 {name=p208 sig_type=std_logic lab=VP}
C {lab_wire.sym} 930 90 2 0 {name=p209 sig_type=std_logic lab=vco_in_4}
C {lab_wire.sym} 770 -130 2 1 {name=p210 sig_type=std_logic lab=vco4_cp_in_en}
C {vsource.sym} 650 -20 0 0 {name=V10 value=1 savecurrent=false}
C {gnd.sym} 650 50 0 0 {name=l10 lab=0
}
C {lab_wire.sym} 890 -130 2 0 {name=p211 sig_type=std_logic lab=nvco4_cp_in_en}
C {lab_wire.sym} 650 -80 2 1 {name=p212 sig_type=std_logic lab=vco4_cp_in_en}
C {lab_wire.sym} 820 150 2 1 {name=p213 sig_type=std_logic lab=vco4_cp_in_en}
C {lab_wire.sym} 820 20 2 1 {name=p214 sig_type=std_logic lab=nvco4_cp_in_en}
C {lab_wire.sym} 260 560 2 1 {name=p215 sig_type=std_logic lab=vco_in_0}
